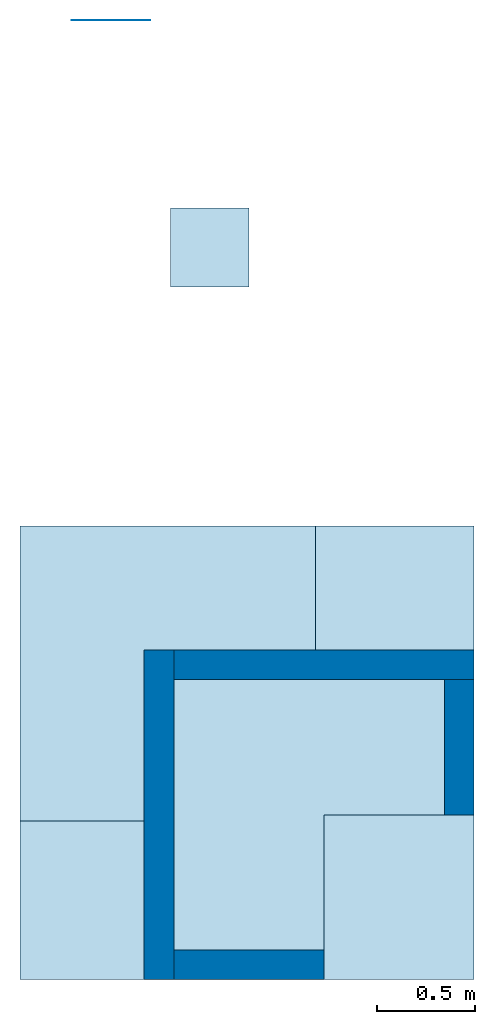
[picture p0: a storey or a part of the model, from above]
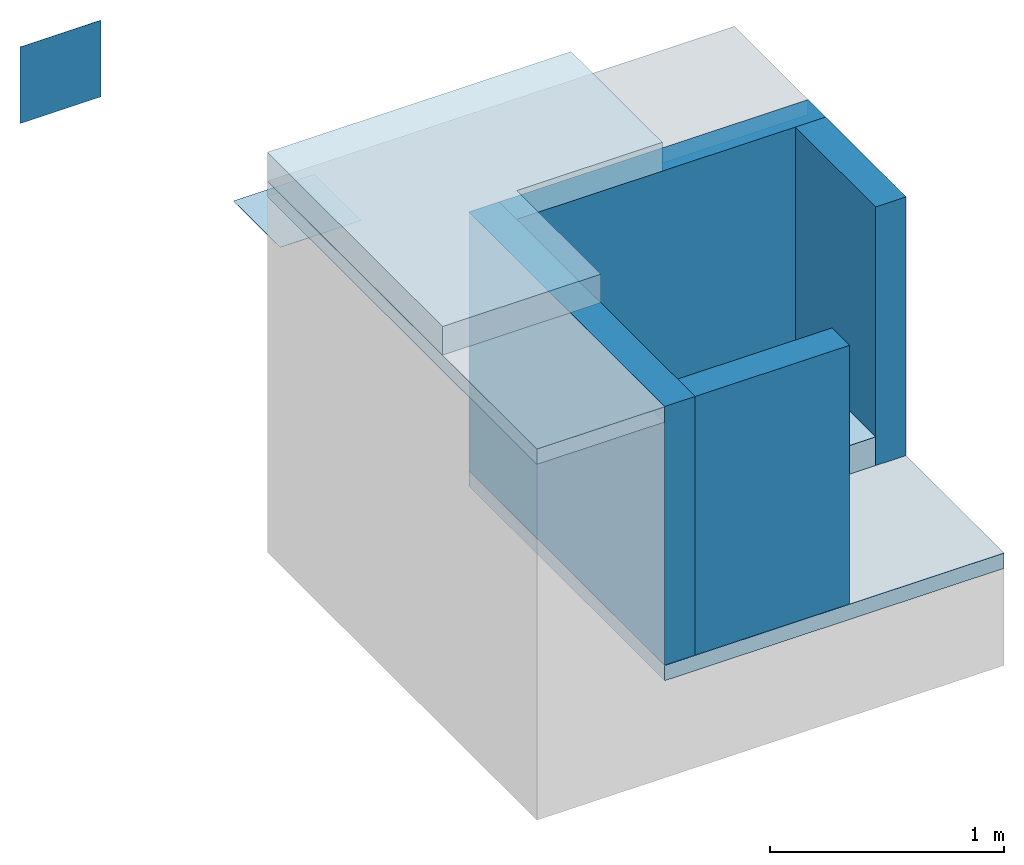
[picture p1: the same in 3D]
Properties of the parts of a building model (IFC2X3)

# File
Description: ViewDefinition [CoordinationView_V2.0], RevitIdentifiers [VersionGUID: f1ee1816-ed1d-4f9e-98e7-7b1e2457fb2f, NumberOfSaves: 22], CoordinateReference [CoordinateBase: Coordenadas compartilhadas]
File name: 0001
Time: 2026-02-18T14:46:59
Written by: ODA IFC SDK 22.8
Made in: 22.1.50.17 - Exporter 22.6.2.0 - IU alternativa 22.6.2.0

# IfcProject, 0001
LongName: Poço de Elevador - Viaplus 1000; Phase: Status do projeto

# IfcSite, Default
RefLatitude: 42, 21, 31, 181944; RefLongitude: -71, -3, -24, -263304; RefElevation: 0 m

# IfcBuilding
Pset_BuildingCommon - NumberOfStoreys: 1; IsLandmarked: no

# IfcBuildingStorey: Nível:Cabeça de 8 mm, ARQ Térreo
LongName: ARQ Térreo; Elevation: -0.0025238 m

# IfcBuildingElementProxy: Modelos genéricos 1:Modelos genéricos 1, Modelos genéricos 1:Modelos genéricos 1:336302
In: ARQ Térreo
Type - Material: #solo, #AMPHIBIA(1), #AMPHIBIA
Pset_BuildingElementProxyCommon - Reference: Modelos genéricos 1; sets with these values: 2
Pset_ProvisionForVoid - Width: 1.675 m; Height: 1.675 m; Depth: 1.675 m

# IfcSlab: Piso:Genérico 150 mm (2)
In: ARQ Térreo
Type - PredefinedType: FLOOR; Material: #concreto 0.15 m
Type - Pset_SlabCommon - IsExternal: no
Pset_QuantityTakeOff - Reference: Genérico 150 mm; sets with these values: 2
Pset_SlabCommon - LoadBearing: no; Reference: Genérico 150 mm; PitchAngle: 0 deg
Name (Piso:Genérico 150 mm:...)
305816
330105

# IfcSlab: Piso:IMPH_AMPHIBIA, Piso:IMPH_AMPHIBIA:330340
In: ARQ Térreo
Type - PredefinedType: FLOOR; Material: #AMPHIBIA 0.0013 m
Type - Pset_SlabCommon - IsExternal: no
Pset_QuantityTakeOff - Reference: IMPH_AMPHIBIA; sets with these values: 2
Pset_SlabCommon - LoadBearing: no; PitchAngle: 0 deg; Reference: IMPH_AMPHIBIA

# IfcSlab: Piso:Lastro (2)
In: ARQ Térreo
Type - PredefinedType: FLOOR; Material: #Argamassa 0.08 m
Type - Pset_SlabCommon - IsExternal: no
Pset_QuantityTakeOff - Reference: Lastro; sets with these values: 2
Pset_SlabCommon - LoadBearing: no; PitchAngle: 0 deg; Reference: Lastro
Name (Piso:Lastro:...)
333752
333855

# IfcWallStandardCase: Parede básica:IMPV_AMPHIBIA, Parede básica:IMPV_VP7000:459587
In: ARQ Térreo
Type - PredefinedType: STANDARD; Material: #AMPHIBIA 0.0013 m
Type - Pset_WallCommon - IsExternal: yes; ThermalTransmittance: 16.4516 kg/K/s3
Pset_QuantityTakeOff - Reference: IMPV_VP7000; sets with these values: 2
Pset_WallCommon - ExtendToStructure: no; LoadBearing: no; Reference: IMPV_VP7000

# IfcWallStandardCase: Parede básica:Parede básica:Parede Concreto (4)
In: ARQ Térreo
Type - PredefinedType: STANDARD; Material: #concreto 0.15 m
Type - Pset_WallCommon - IsExternal: yes; ThermalTransmittance: 6.97333 kg/K/s3
Pset_QuantityTakeOff - sets with these values: 2
Pset_WallCommon - ExtendToStructure: no; LoadBearing: no
Name (Parede básica:...) | Pset_QuantityTakeOff, Reference = Pset_WallCommon, Reference
Parede Concreto:395312 | Parede Concreto
Parede básica:Parede Concreto:332534 | Parede básica:Parede Concreto
Parede básica:Parede Concreto:333110 | Parede básica:Parede Concreto
Parede básica:Parede Concreto:333339 | Parede básica:Parede Concreto
